VERSION 5.7 ;
  NOWIREEXTENSIONATPIN ON ;
  DIVIDERCHAR "/" ;
  BUSBITCHARS "[]" ;
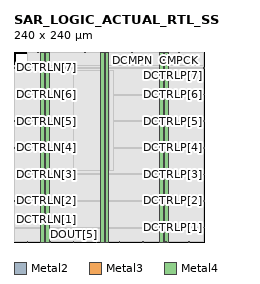
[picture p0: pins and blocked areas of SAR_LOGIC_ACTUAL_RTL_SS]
MACRO SAR_LOGIC_ACTUAL_RTL_SS
  CLASS BLOCK ;
  FOREIGN SAR_LOGIC_ACTUAL_RTL_SS ;
  ORIGIN 0.000 0.000 ;
  SIZE 240.000 BY 240.000 ;
  PIN CLKS
    DIRECTION INPUT ;
    USE SIGNAL ;
    ANTENNAGATEAREA 9.476000 ;
    ANTENNADIFFAREA 0.820800 ;
    PORT
      LAYER Metal2 ;
        RECT 30.240 239.440 30.800 240.000 ;
    END
  END CLKS
  PIN CMPCK
    DIRECTION OUTPUT ;
    USE SIGNAL ;
    ANTENNADIFFAREA 2.069600 ;
    PORT
      LAYER Metal2 ;
        RECT 208.320 239.440 208.880 240.000 ;
    END
  END CMPCK
  PIN DCMPN
    DIRECTION INPUT ;
    USE SIGNAL ;
    ANTENNAGATEAREA 9.476000 ;
    ANTENNADIFFAREA 0.820800 ;
    PORT
      LAYER Metal2 ;
        RECT 148.960 239.440 149.520 240.000 ;
    END
  END DCMPN
  PIN DCMPP
    DIRECTION INPUT ;
    USE SIGNAL ;
    ANTENNAGATEAREA 9.476000 ;
    ANTENNADIFFAREA 0.820800 ;
    PORT
      LAYER Metal2 ;
        RECT 89.600 239.440 90.160 240.000 ;
    END
  END DCMPP
  PIN DCTRLN[1]
    DIRECTION OUTPUT ;
    USE SIGNAL ;
    ANTENNADIFFAREA 2.365600 ;
    PORT
      LAYER Metal3 ;
        RECT 0.000 17.920 0.560 18.480 ;
    END
  END DCTRLN[1]
  PIN DCTRLN[2]
    DIRECTION OUTPUT ;
    USE SIGNAL ;
    ANTENNADIFFAREA 2.365600 ;
    PORT
      LAYER Metal3 ;
        RECT 0.000 51.520 0.560 52.080 ;
    END
  END DCTRLN[2]
  PIN DCTRLN[3]
    DIRECTION OUTPUT ;
    USE SIGNAL ;
    ANTENNADIFFAREA 2.365600 ;
    PORT
      LAYER Metal3 ;
        RECT 0.000 85.120 0.560 85.680 ;
    END
  END DCTRLN[3]
  PIN DCTRLN[4]
    DIRECTION OUTPUT ;
    USE SIGNAL ;
    ANTENNADIFFAREA 2.365600 ;
    PORT
      LAYER Metal3 ;
        RECT 0.000 118.720 0.560 119.280 ;
    END
  END DCTRLN[4]
  PIN DCTRLN[5]
    DIRECTION OUTPUT ;
    USE SIGNAL ;
    ANTENNADIFFAREA 2.365600 ;
    PORT
      LAYER Metal3 ;
        RECT 0.000 152.320 0.560 152.880 ;
    END
  END DCTRLN[5]
  PIN DCTRLN[6]
    DIRECTION OUTPUT ;
    USE SIGNAL ;
    ANTENNADIFFAREA 2.365600 ;
    PORT
      LAYER Metal3 ;
        RECT 0.000 185.920 0.560 186.480 ;
    END
  END DCTRLN[6]
  PIN DCTRLN[7]
    DIRECTION OUTPUT ;
    USE SIGNAL ;
    ANTENNADIFFAREA 2.365600 ;
    PORT
      LAYER Metal3 ;
        RECT 0.000 219.520 0.560 220.080 ;
    END
  END DCTRLN[7]
  PIN DCTRLP[1]
    DIRECTION OUTPUT ;
    USE SIGNAL ;
    ANTENNADIFFAREA 2.365600 ;
    PORT
      LAYER Metal3 ;
        RECT 239.440 17.920 240.000 18.480 ;
    END
  END DCTRLP[1]
  PIN DCTRLP[2]
    DIRECTION OUTPUT ;
    USE SIGNAL ;
    ANTENNADIFFAREA 2.365600 ;
    PORT
      LAYER Metal3 ;
        RECT 239.440 51.520 240.000 52.080 ;
    END
  END DCTRLP[2]
  PIN DCTRLP[3]
    DIRECTION OUTPUT ;
    USE SIGNAL ;
    ANTENNADIFFAREA 2.365600 ;
    PORT
      LAYER Metal3 ;
        RECT 239.440 85.120 240.000 85.680 ;
    END
  END DCTRLP[3]
  PIN DCTRLP[4]
    DIRECTION OUTPUT ;
    USE SIGNAL ;
    ANTENNADIFFAREA 2.365600 ;
    PORT
      LAYER Metal3 ;
        RECT 239.440 118.720 240.000 119.280 ;
    END
  END DCTRLP[4]
  PIN DCTRLP[5]
    DIRECTION OUTPUT ;
    USE SIGNAL ;
    ANTENNADIFFAREA 2.365600 ;
    PORT
      LAYER Metal3 ;
        RECT 239.440 152.320 240.000 152.880 ;
    END
  END DCTRLP[5]
  PIN DCTRLP[6]
    DIRECTION OUTPUT ;
    USE SIGNAL ;
    ANTENNADIFFAREA 2.365600 ;
    PORT
      LAYER Metal3 ;
        RECT 239.440 185.920 240.000 186.480 ;
    END
  END DCTRLP[6]
  PIN DCTRLP[7]
    DIRECTION OUTPUT ;
    USE SIGNAL ;
    ANTENNADIFFAREA 2.365600 ;
    PORT
      LAYER Metal3 ;
        RECT 239.440 219.520 240.000 220.080 ;
    END
  END DCTRLP[7]
  PIN DOUT[0]
    DIRECTION OUTPUT ;
    USE SIGNAL ;
    ANTENNADIFFAREA 2.365600 ;
    PORT
      LAYER Metal2 ;
        RECT 220.640 0.000 221.200 0.560 ;
    END
  END DOUT[0]
  PIN DOUT[1]
    DIRECTION OUTPUT ;
    USE SIGNAL ;
    ANTENNADIFFAREA 2.365600 ;
    PORT
      LAYER Metal2 ;
        RECT 191.520 0.000 192.080 0.560 ;
    END
  END DOUT[1]
  PIN DOUT[2]
    DIRECTION OUTPUT ;
    USE SIGNAL ;
    ANTENNADIFFAREA 2.365600 ;
    PORT
      LAYER Metal2 ;
        RECT 162.400 0.000 162.960 0.560 ;
    END
  END DOUT[2]
  PIN DOUT[3]
    DIRECTION OUTPUT ;
    USE SIGNAL ;
    ANTENNADIFFAREA 2.365600 ;
    PORT
      LAYER Metal2 ;
        RECT 133.280 0.000 133.840 0.560 ;
    END
  END DOUT[3]
  PIN DOUT[4]
    DIRECTION OUTPUT ;
    USE SIGNAL ;
    ANTENNADIFFAREA 2.365600 ;
    PORT
      LAYER Metal2 ;
        RECT 104.160 0.000 104.720 0.560 ;
    END
  END DOUT[4]
  PIN DOUT[5]
    DIRECTION OUTPUT ;
    USE SIGNAL ;
    ANTENNADIFFAREA 2.365600 ;
    PORT
      LAYER Metal2 ;
        RECT 75.040 0.000 75.600 0.560 ;
    END
  END DOUT[5]
  PIN DOUT[6]
    DIRECTION OUTPUT ;
    USE SIGNAL ;
    ANTENNADIFFAREA 2.365600 ;
    PORT
      LAYER Metal2 ;
        RECT 45.920 0.000 46.480 0.560 ;
    END
  END DOUT[6]
  PIN DOUT[7]
    DIRECTION OUTPUT ;
    USE SIGNAL ;
    ANTENNADIFFAREA 2.365600 ;
    PORT
      LAYER Metal2 ;
        RECT 16.800 0.000 17.360 0.560 ;
    END
  END DOUT[7]
  PIN VDD
    DIRECTION INOUT ;
    USE POWER ;
    PORT
      LAYER Metal4 ;
        RECT 33.980 0.000 38.980 240.000 ;
    END
    PORT
      LAYER Metal4 ;
        RECT 108.980 0.000 113.980 240.000 ;
    END
    PORT
      LAYER Metal4 ;
        RECT 183.980 0.000 188.980 240.000 ;
    END
  END VDD
  PIN VSS
    DIRECTION INOUT ;
    USE GROUND ;
    PORT
      LAYER Metal4 ;
        RECT 39.980 0.000 44.980 240.000 ;
    END
    PORT
      LAYER Metal4 ;
        RECT 114.980 0.000 119.980 240.000 ;
    END
    PORT
      LAYER Metal4 ;
        RECT 189.980 0.000 194.980 240.000 ;
    END
  END VSS
  OBS
      LAYER Nwell ;
        RECT 19.730 23.090 219.950 219.950 ;
      LAYER Metal1 ;
        RECT 20.160 23.220 219.520 219.820 ;
      LAYER Metal2 ;
        RECT 16.940 239.140 29.940 239.440 ;
        RECT 31.100 239.140 89.300 239.440 ;
        RECT 90.460 239.140 148.660 239.440 ;
        RECT 149.820 239.140 208.020 239.440 ;
        RECT 209.180 239.140 239.540 239.440 ;
        RECT 16.940 0.860 239.540 239.140 ;
        RECT 17.660 0.560 45.620 0.860 ;
        RECT 46.780 0.560 74.740 0.860 ;
        RECT 75.900 0.560 103.860 0.860 ;
        RECT 105.020 0.560 132.980 0.860 ;
        RECT 134.140 0.560 162.100 0.860 ;
        RECT 163.260 0.560 191.220 0.860 ;
        RECT 192.380 0.560 220.340 0.860 ;
        RECT 221.500 0.560 239.540 0.860 ;
      LAYER Metal3 ;
        RECT 0.560 220.380 239.590 222.740 ;
        RECT 0.860 219.220 239.140 220.380 ;
        RECT 0.560 186.780 239.590 219.220 ;
        RECT 0.860 185.620 239.140 186.780 ;
        RECT 0.560 153.180 239.590 185.620 ;
        RECT 0.860 152.020 239.140 153.180 ;
        RECT 0.560 119.580 239.590 152.020 ;
        RECT 0.860 118.420 239.140 119.580 ;
        RECT 0.560 85.980 239.590 118.420 ;
        RECT 0.860 84.820 239.140 85.980 ;
        RECT 0.560 52.380 239.590 84.820 ;
        RECT 0.860 51.220 239.140 52.380 ;
        RECT 0.560 18.780 239.590 51.220 ;
        RECT 0.860 17.620 239.140 18.780 ;
        RECT 0.560 0.700 239.590 17.620 ;
      LAYER Metal4 ;
        RECT 75.740 90.250 108.680 216.630 ;
        RECT 114.280 90.250 114.680 216.630 ;
        RECT 120.280 90.250 125.300 216.630 ;
  END
END SAR_LOGIC_ACTUAL_RTL_SS
END LIBRARY

